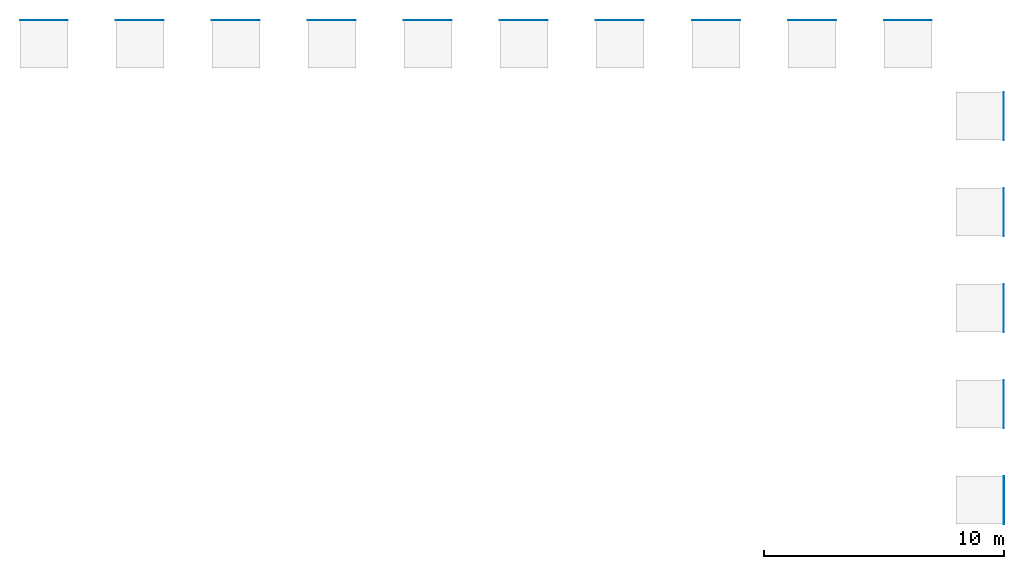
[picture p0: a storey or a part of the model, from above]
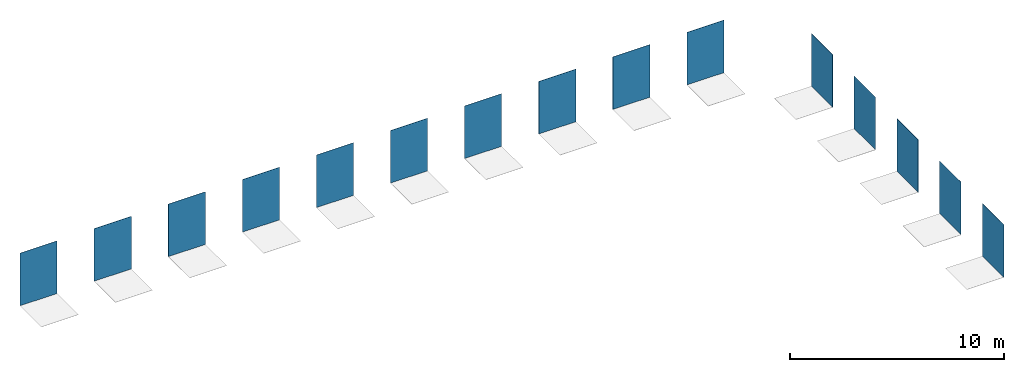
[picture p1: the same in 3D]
Properties of the parts of a building model (IFC2X3), part 2 of 2

# IfcWallStandardCase: Basic Wall:PGR_Porcelanosa_CeramicTiles_Ascot_Arce-193x1200mm-100161043, Basic Wall:PGR_Porcelanosa_CeramicTiles_Ascot_Arce-193x1200mm-100161043:215110
Type - NBS_Data - HasSurfaceRoughness: no; AbrasionResistance: 4: Light-External Access; BreakingStrength: Average Value: 3310 N (Min. 1300 N); ChemicalResistance: Class 'A' for swimming pools and cleaning products (resists attack); minimum Class 'B' for acids and bases; Collection: PAR-KER; CreationDate: 2018/07; Dcof: >0.42; FlexuralStrength: >40 N/mm²; FrostResistance: Conforms to ISO 10545-9; Group: BIa; MoistureExpansion: <0.1 mm/m; RampTest: R-10; RecycledContent: >6.5%; Series: Ascot; SlipResistanceValuePendulumTestValue: CL1; StainResistance: Class 5: Easy cleaning with water; SurfaceQuality: Without surface defects; ThermalShockResistance: Conforms to ISO 10545–12; UpecC: n/a; UpecE: n/a; UpecP: n/a; UpecU: n/a; WaterAbsorption: E<=0.5%
COBie - AssetIdentifier: n/a; BarCode: n/a; InstallationDate: 1900-12-31T23:59:59; TagNumber: n/a; WarrantyStartDate: 1900-12-31T23:59:59

# IfcWallStandardCase: Basic Wall:PGR_Porcelanosa_CeramicTiles_Ascot_Arce-294x1200mm-100161044, Basic Wall:PGR_Porcelanosa_CeramicTiles_Ascot_Arce-294x1200mm-100161044:215111
In: Level 1
Type - PredefinedType: STANDARD; Material: PGR_Porcelanosa_CeramicTiles_Ascot_Arce-294x1200mm-100161044 11 mm
Type - NBS_General - Author: Porcelanosa Group; BIMObjectName: PGR_Porcelanosa_CeramicTiles_Ascot_Arce-294x1200mm-100161044; ManufacturerURL: www.porcelanosa.com; NBSDescription: Ceramic Tiles; NBSReference: 45-80-95/310; ProductInformation: http://calidad.info-grupo.com:8081/GeneraFicha3/PDF?articulo=100161044&lang=EN&un=0; Revision: n/a; Uniclass2015Code: Pr_35_93_96_19; Uniclass2015Title: Ceramic Tiles; Uniclass2015Version: Products v1.5; Version: 1
Type - COBie - AccessibilityPerformance: See ProductInformation (Technical PDF); AssetType: Fixed; Category: Walls; CodePerformance: ISO-13006:2012; UNE-EN 14411:2012; Color: Marron; Constituents: Clays, feldespat and glaze; Description: Rectified Porcelain tiles, ASCOT series from PORCELANOSA, MARRON color and MATTE finish, 29.4x120 cm (11.5 mm thickness), group BIa, according to UNE-EN 14411, water absortion capacity E<=0.5%, flexural strength >40 N/mm², breaking strength with an average value of 3310 N (Min. 1300 N) and slip resistance R-10; DurationUnit: year; ExpectedLife: 50; Features: See ProductInformation (Technical PDF); Grade: First quality; Manufacturer: bim.gp@porcelanosagrupo.com; ModelNumber: 100161044; ModelReference: Ascot Arce 29.4x120 cm; Name: CeramicTiles_Ascot_Arce-294x1200mm-100161044; NominalHeight: 11.5 mm; NominalLength: 1200 mm; NominalWidth: 294 mm; ReplacementCost: n/a; Shape: Rectangular; Size: 294x1200x11.5 mm; Sustainability Performance: See ProductInformation (Technical PDF); WarrantyDescription: Manufacturer warranty, applicable worldwide, with the pertinent national legislation prevailing in all cases and covering at least a 3-year period; all products must have been manufactured and fitted in accordance with the Fabricator's Manual, and have been used and cared for in accordance with the Guide to Use, Cleaning and Care available on the web page www.porcelanosa.com; WarrantyDurationLabor: n/a; WarrantyDurationParts: 3; WarrantyDurationUnit: year; WarrantyGuarantorLabor: n/a; WarrantyGuarantorParts: bim.gp@porcelanosagrupo.com
Type - Pset_CoveringCommon - IsExternal: yes; Reference: n/a; AcousticRating: n/a; Finish: Tone Variations, Matte, Rectified, Wood; FireRating: A1; FlammabilityRating: Class 0; FragilityRating: n/a; Material: Ceramic; SurfaceSpreadOfFlame: Class 0; ThermalTransmittance: 200 kg/K/s3; TotalThickness: 11.5 mm
Type - IFC - IfcExportType: FLOORING; IfcExportAS: IfcCovering
Type - NBS_Data - HasSurfaceRoughness: no; AbrasionResistance: 4: Light-External Access; BreakingStrength: Average Value: 3310 N (Min. 1300 N); ChemicalResistance: Class 'A' for swimming pools and cleaning products (resists attack); minimum Class 'B' for acids and bases; Collection: PAR-KER; CreationDate: 2018/07; Dcof: >0.42; FlexuralStrength: >40 N/mm²; FrostResistance: Conforms to ISO 10545-9; Group: BIa; MoistureExpansion: <0.1 mm/m; RampTest: R-10; RecycledContent: >6.5%; Series: Ascot; SlipResistanceValuePendulumTestValue: CL1; StainResistance: Class 5: Easy cleaning with water; SurfaceQuality: Without surface defects; ThermalShockResistance: Conforms to ISO 10545–12; UpecC: 2; UpecE: 3; UpecP: 3; UpecU: 3; WaterAbsorption: E<=0.5%
COBie - AssetIdentifier: n/a; BarCode: n/a; InstallationDate: 1900-12-31T23:59:59; TagNumber: n/a; WarrantyStartDate: 1900-12-31T23:59:59

# IfcWallStandardCase: Basic Wall:PGR_Porcelanosa_CeramicTiles_Ascot_Arce_Ant.-193x1200mm-100161045, Basic Wall:PGR_Porcelanosa_CeramicTiles_Ascot_Arce_Ant.-193x1200mm-100161045:215112
In: Level 1
Type - PredefinedType: STANDARD; Material: PGR_Porcelanosa_CeramicTiles_Ascot_Arce_Ant.-193x1200mm-100161045 11 mm
Type - NBS_General - Author: Porcelanosa Group; BIMObjectName: PGR_Porcelanosa_CeramicTiles_Ascot_Arce_Ant.-193x1200mm-100161045; ManufacturerURL: www.porcelanosa.com; NBSDescription: Ceramic Tiles; NBSReference: 45-80-95/310; ProductInformation: http://calidad.info-grupo.com:8081/GeneraFicha3/PDF?articulo=100161045&lang=EN&un=0; Revision: n/a; Uniclass2015Code: Pr_35_93_96_19; Uniclass2015Title: Ceramic Tiles; Uniclass2015Version: Products v1.5; Version: 1
Type - COBie - AccessibilityPerformance: See ProductInformation (Technical PDF); AssetType: Fixed; Category: Pr_35_93_96_19:Ceramic Tiles; CodePerformance: ISO-13006:2012; UNE-EN 14411:2012; Color: Marron; Constituents: Clays, feldespat and glaze; Description: Rectified Porcelain tiles, ASCOT series from PORCELANOSA, MARRON color and MATTE finish, 19.3x120 cm (11.5 mm thickness), group BIa, according to UNE-EN 14411, water absortion capacity E<=0.5%, flexural strength >40 N/mm², breaking strength with an average value of 3310 N (Min. 1300 N) and slip resistance R-12; DurationUnit: year; ExpectedLife: 50; Features: See ProductInformation (Technical PDF); Grade: First quality; Manufacturer: bim.gp@porcelanosagrupo.com; ModelNumber: 100161045; ModelReference: Ascot Arce Ant. 19.3x120 cm; Name: CeramicTiles_Ascot_Arce_Ant.-193x1200mm-100161045; NominalHeight: 11.5 mm; NominalLength: 1200 mm; NominalWidth: 193 mm; ReplacementCost: n/a; Shape: Rectangular; Size: 193x1200x11.5 mm; Sustainability Performance: See ProductInformation (Technical PDF); WarrantyDescription: Manufacturer warranty, applicable worldwide, with the pertinent national legislation prevailing in all cases and covering at least a 3-year period; all products must have been manufactured and fitted in accordance with the Fabricator's Manual, and have been used and cared for in accordance with the Guide to Use, Cleaning and Care available on the web page www.porcelanosa.com; WarrantyDurationLabor: n/a; WarrantyDurationParts: 3; WarrantyDurationUnit: year; WarrantyGuarantorLabor: n/a; WarrantyGuarantorParts: bim.gp@porcelanosagrupo.com
Type - Pset_CoveringCommon - IsExternal: yes; Reference: n/a; AcousticRating: n/a; Finish: Tone Variations, Matte, Non-Slip, Rectified, Wood; FireRating: A1; FlammabilityRating: Class 0; FragilityRating: n/a; Material: Ceramic; SurfaceSpreadOfFlame: Class 0; ThermalTransmittance: 200 kg/K/s3; TotalThickness: 11.5 mm
Type - IFC - IfcExportType: FLOORING; IfcExportAS: IfcCovering
Type - NBS_Data - HasSurfaceRoughness: no; AbrasionResistance: 4: Light-External Access; BreakingStrength: Average Value: 3310 N (Min. 1300 N); ChemicalResistance: Class 'A' for swimming pools and cleaning products (resists attack); minimum Class 'B' for acids and bases; Collection: PAR-KER; CreationDate: 2018/07; Dcof: >0.42; FlexuralStrength: >40 N/mm²; FrostResistance: Conforms to ISO 10545-9; Group: BIa; MoistureExpansion: <0.1 mm/m; RampTest: R-12; RecycledContent: >6.5%; Series: Ascot; SlipResistanceValuePendulumTestValue: CL3; StainResistance: Class 5: Easy cleaning with water; SurfaceQuality: Without surface defects; ThermalShockResistance: Conforms to ISO 10545–12; UpecC: n/a; UpecE: n/a; UpecP: n/a; UpecU: n/a; WaterAbsorption: E<=0.5%
COBie - AssetIdentifier: n/a; BarCode: n/a; InstallationDate: 1900-12-31T23:59:59; TagNumber: n/a; WarrantyStartDate: 1900-12-31T23:59:59

# IfcWallStandardCase: Basic Wall:PGR_Porcelanosa_CeramicTiles_Ascot_Grey-193x1200mm-100161025, Basic Wall:PGR_Porcelanosa_CeramicTiles_Ascot_Grey-193x1200mm-100161025:212342
In: Level 1
Type - PredefinedType: STANDARD; Material: PGR_Porcelanosa_CeramicTiles_Ascot_Grey-193x1200mm-100161025 12 mm
Type - NBS_General - Author: Porcelanosa Group; BIMObjectName: PGR_Porcelanosa_CeramicTiles_Ascot_Grey-193x1200mm-100161025; ManufacturerURL: www.porcelanosa.com; NBSDescription: Ceramic Tiles; NBSReference: 45-80-95/310; ProductInformation: http://calidad.info-grupo.com:8081/GeneraFicha3/PDF?articulo=100161025&lang=EN&un=0; Revision: n/a; Uniclass2015Code: Pr_35_93_96_19; Uniclass2015Title: Ceramic Tiles; Uniclass2015Version: Products v1.5; Version: 1
Type - COBie - AccessibilityPerformance: See ProductInformation (Technical PDF); AssetType: Fixed; Category: Walls; CodePerformance: ISO-13006:2012; UNE-EN 14411:2012; Color: Gris; Constituents: Clays, feldespat and glaze; Description: Rectified Porcelain tiles, ASCOT series from PORCELANOSA, GRIS color and MATTE finish, 19.3x120 cm (11.5 mm thickness), group BIa, according to UNE-EN 14411, water absortion capacity E<=0.5%, flexural strength >40 N/mm², breaking strength with an average value of 3310 N (Min. 1300 N) and slip resistance R-10; DurationUnit: year; ExpectedLife: 50; Features: See ProductInformation (Technical PDF); Grade: First quality; Manufacturer: bim.gp@porcelanosagrupo.com; ModelNumber: 100161025; ModelReference: Ascot Grey 19.3x120 cm; Name: CeramicTiles_Ascot_Grey-193x1200mm-100161025; NominalHeight: 11.5 mm; NominalLength: 1200 mm; NominalWidth: 193 mm; ReplacementCost: n/a; Shape: Rectangular; Size: 193x1200x11.5 mm; Sustainability Performance: See ProductInformation (Technical PDF); WarrantyDescription: Manufacturer warranty, applicable worldwide, with the pertinent national legislation prevailing in all cases and covering at least a 3-year period; all products must have been manufactured and fitted in accordance with the Fabricator's Manual, and have been used and cared for in accordance with the Guide to Use, Cleaning and Care available on the web page www.porcelanosa.com; WarrantyDurationLabor: n/a; WarrantyDurationParts: 3; WarrantyDurationUnit: year; WarrantyGuarantorLabor: n/a; WarrantyGuarantorParts: bim.gp@porcelanosagrupo.com
Type - Pset_CoveringCommon - IsExternal: yes; Reference: n/a; AcousticRating: n/a; Finish: Tone Variations, Matte, Rectified, Wood; FireRating: A1; FlammabilityRating: Class 0; FragilityRating: n/a; Material: Ceramic; SurfaceSpreadOfFlame: Class 0; ThermalTransmittance: 200 kg/K/s3; TotalThickness: 11.5 mm
Type - IFC - IfcExportType: FLOORING; IfcExportAS: IfcCovering
Type - NBS_Data - HasSurfaceRoughness: no; AbrasionResistance: 4: Light-External Access; BreakingStrength: Average Value: 3310 N (Min. 1300 N); ChemicalResistance: Class 'A' for swimming pools and cleaning products (resists attack); minimum Class 'B' for acids and bases; Collection: PAR-KER; CreationDate: 2018/07; Dcof: >0.42; FlexuralStrength: >40 N/mm²; FrostResistance: Conforms to ISO 10545-9; Group: BIa; MoistureExpansion: <0.1 mm/m; RampTest: R-10; RecycledContent: >6.5%; Series: Ascot; SlipResistanceValuePendulumTestValue: CL1; StainResistance: Class 5: Easy cleaning with water; SurfaceQuality: Without surface defects; ThermalShockResistance: Conforms to ISO 10545–12; UpecC: n/a; UpecE: n/a; UpecP: n/a; UpecU: n/a; WaterAbsorption: E<=0.5%
COBie - AssetIdentifier: n/a; BarCode: n/a; InstallationDate: 1900-12-31T23:59:59; TagNumber: n/a; WarrantyStartDate: 1900-12-31T23:59:59

# IfcWallStandardCase: Basic Wall:PGR_Porcelanosa_CeramicTiles_Ascot_Grey-294x1200mm-100161120, Basic Wall:PGR_Porcelanosa_CeramicTiles_Ascot_Grey-294x1200mm-100161120:212256
In: Level 1
Type - PredefinedType: STANDARD; Material: PGR_Porcelanosa_CeramicTiles_Ascot_Grey-294x1200mm-100161120 12 mm
Type - NBS_General - Author: Porcelanosa Group; BIMObjectName: PGR_Porcelanosa_CeramicTiles_Ascot_Grey-294x1200mm-100161120; ManufacturerURL: www.porcelanosa.com; NBSDescription: Ceramic Tiles; NBSReference: 45-80-95/310; ProductInformation: http://calidad.info-grupo.com:8081/GeneraFicha3/PDF?articulo=100161120&lang=EN&un=0; Revision: n/a; Uniclass2015Code: Pr_35_93_96_19; Uniclass2015Title: Ceramic Tiles; Uniclass2015Version: Products v1.5; Version: 1
Type - COBie - AccessibilityPerformance: See ProductInformation (Technical PDF); AssetType: Fixed; Category: Pr_35_93_96_19:Ceramic Tiles; CodePerformance: ISO-13006:2012; UNE-EN 14411:2012; Color: Gris; Constituents: Clays, feldespat and glaze; Description: Rectified Porcelain tiles, ASCOT series from PORCELANOSA, GRIS color and MATTE finish, 29.4x120 cm (11.5 mm thickness), group BIa, according to UNE-EN 14411, water absortion capacity E<=0.5%, flexural strength >40 N/mm², breaking strength with an average value of 3310 N (Min. 1300 N) and slip resistance R-10; DurationUnit: year; ExpectedLife: 50; Features: See ProductInformation (Technical PDF); Grade: First quality; Manufacturer: bim.gp@porcelanosagrupo.com; ModelNumber: 100161120; ModelReference: Ascot Grey 29.4x120 cm; Name: CeramicTiles_Ascot_Grey-294x1200mm-100161120; NominalHeight: 11.5 mm; NominalLength: 1200 mm; NominalWidth: 294 mm; ReplacementCost: n/a; Shape: Rectangular; Size: 294x1200x11.5 mm; Sustainability Performance: See ProductInformation (Technical PDF); WarrantyDescription: Manufacturer warranty, applicable worldwide, with the pertinent national legislation prevailing in all cases and covering at least a 3-year period; all products must have been manufactured and fitted in accordance with the Fabricator's Manual, and have been used and cared for in accordance with the Guide to Use, Cleaning and Care available on the web page www.porcelanosa.com; WarrantyDurationLabor: n/a; WarrantyDurationParts: 3; WarrantyDurationUnit: year; WarrantyGuarantorLabor: n/a; WarrantyGuarantorParts: bim.gp@porcelanosagrupo.com
Type - Pset_CoveringCommon - IsExternal: yes; Reference: n/a; AcousticRating: n/a; Finish: Tone Variations, Matte, Rectified, Wood; FireRating: A1; FlammabilityRating: Class 0; FragilityRating: n/a; Material: Ceramic; SurfaceSpreadOfFlame: Class 0; ThermalTransmittance: 200 kg/K/s3; TotalThickness: 11.5 mm
Type - IFC - IfcExportType: FLOORING; IfcExportAS: IfcCovering
Type - NBS_Data - HasSurfaceRoughness: no; AbrasionResistance: 4: Light-External Access; BreakingStrength: Average Value: 3310 N (Min. 1300 N); ChemicalResistance: Class 'A' for swimming pools and cleaning products (resists attack); minimum Class 'B' for acids and bases; Collection: PAR-KER; CreationDate: 2018/07; Dcof: >0.42; FlexuralStrength: >40 N/mm²; FrostResistance: Conforms to ISO 10545-9; Group: BIa; MoistureExpansion: <0.1 mm/m; RampTest: R-10; RecycledContent: >6.5%; Series: Ascot; SlipResistanceValuePendulumTestValue: CL1; StainResistance: Class 5: Easy cleaning with water; SurfaceQuality: Without surface defects; ThermalShockResistance: Conforms to ISO 10545–12; UpecC: 2; UpecE: 3; UpecP: 3; UpecU: 2S; WaterAbsorption: E<=0.5%
COBie - AssetIdentifier: n/a; BarCode: n/a; InstallationDate: 1900-12-31T23:59:59; TagNumber: n/a; WarrantyStartDate: 1900-12-31T23:59:59

# IfcWallStandardCase: Basic Wall:PGR_Porcelanosa_CeramicTiles_Ascot_Grey_Ant.-193x1200mm-100161026, Basic Wall:PGR_Porcelanosa_CeramicTiles_Ascot_Grey_Ant.-193x1200mm-100161026:213212
In: Level 1
Type - PredefinedType: STANDARD; Material: PGR_Porcelanosa_CeramicTiles_Ascot_Grey_Ant.-193x1200mm-100161026 12 mm
Type - NBS_General - Author: Porcelanosa Group; BIMObjectName: PGR_Porcelanosa_CeramicTiles_Ascot_Grey_Ant.-193x1200mm-100161026; ManufacturerURL: www.porcelanosa.com; NBSDescription: Ceramic Tiles; NBSReference: 45-80-95/310; ProductInformation: http://calidad.info-grupo.com:8081/GeneraFicha3/PDF?articulo=100161026&lang=EN&un=0; Revision: n/a; Uniclass2015Code: Pr_35_93_96_19; Uniclass2015Title: Ceramic Tiles; Uniclass2015Version: Products v1.5; Version: 1
Type - COBie - AccessibilityPerformance: See ProductInformation (Technical PDF); AssetType: Fixed; Category: Walls; CodePerformance: ISO-13006:2012; UNE-EN 14411:2012; Color: Gris; Constituents: Clays, feldespat and glaze; Description: Rectified Porcelain tiles, ASCOT series from PORCELANOSA, GRIS color and MATTE finish, 19.3x120 cm (11.5 mm thickness), group BIa, according to UNE-EN 14411, water absortion capacity E<=0.5%, flexural strength >40 N/mm², breaking strength with an average value of 3310 N (Min. 1300 N) and slip resistance R-12; DurationUnit: year; ExpectedLife: 50; Features: See ProductInformation (Technical PDF); Grade: First quality; Manufacturer: bim.gp@porcelanosagrupo.com; ModelNumber: 100161026; ModelReference: Ascot Grey Ant. 19.3x120 cm; Name: CeramicTiles_Ascot_Grey_Ant.-193x1200mm-100161026; NominalHeight: 11.5 mm; NominalLength: 1200 mm; NominalWidth: 193 mm; ReplacementCost: n/a; Shape: Rectangular; Size: 193x1200x11.5 mm; Sustainability Performance: See ProductInformation (Technical PDF); WarrantyDescription: Manufacturer warranty, applicable worldwide, with the pertinent national legislation prevailing in all cases and covering at least a 3-year period; all products must have been manufactured and fitted in accordance with the Fabricator's Manual, and have been used and cared for in accordance with the Guide to Use, Cleaning and Care available on the web page www.porcelanosa.com; WarrantyDurationLabor: n/a; WarrantyDurationParts: 3; WarrantyDurationUnit: year; WarrantyGuarantorLabor: n/a; WarrantyGuarantorParts: bim.gp@porcelanosagrupo.com
Type - Pset_CoveringCommon - IsExternal: yes; Reference: n/a; AcousticRating: n/a; Finish: Tone Variations, Matte, Non-Slip, Rectified, Wood; FireRating: A1; FlammabilityRating: Class 0; FragilityRating: n/a; Material: Ceramic; SurfaceSpreadOfFlame: Class 0; ThermalTransmittance: 200 kg/K/s3; TotalThickness: 11.5 mm
Type - IFC - IfcExportType: FLOORING; IfcExportAS: IfcCovering
Type - NBS_Data - HasSurfaceRoughness: no; AbrasionResistance: 4: Light-External Access; BreakingStrength: Average Value: 3310 N (Min. 1300 N); ChemicalResistance: Class 'A' for swimming pools and cleaning products (resists attack); minimum Class 'B' for acids and bases; Collection: PAR-KER; CreationDate: 2018/07; Dcof: >0.42; FlexuralStrength: >40 N/mm²; FrostResistance: Conforms to ISO 10545-9; Group: BIa; MoistureExpansion: <0.1 mm/m; RampTest: R-12; RecycledContent: >6.5%; Series: Ascot; SlipResistanceValuePendulumTestValue: CL3; StainResistance: Class 5: Easy cleaning with water; SurfaceQuality: Without surface defects; ThermalShockResistance: Conforms to ISO 10545–12; UpecC: n/a; UpecE: n/a; UpecP: n/a; UpecU: n/a; WaterAbsorption: E<=0.5%
COBie - AssetIdentifier: n/a; BarCode: n/a; InstallationDate: 1900-12-31T23:59:59; TagNumber: n/a; WarrantyStartDate: 1900-12-31T23:59:59

# IfcWallStandardCase: Basic Wall:PGR_Porcelanosa_CeramicTiles_Ascot_Olivo-193x1200mm-100161027, Basic Wall:PGR_Porcelanosa_CeramicTiles_Ascot_Olivo-193x1200mm-100161027:209160
In: Level 1
Type - PredefinedType: STANDARD; Material: PGR_Porcelanosa_CeramicTiles_Ascot_Olivo-193x1200mm-100161027 12 mm
Type - NBS_General - Author: Porcelanosa Group; BIMObjectName: PGR_Porcelanosa_CeramicTiles_Ascot_Olivo-193x1200mm-100161027; ManufacturerURL: www.porcelanosa.com; NBSDescription: Ceramic Tiles; NBSReference: 45-80-95/310; ProductInformation: http://calidad.info-grupo.com:8081/GeneraFicha3/PDF?articulo=100161027&lang=EN&un=0; Revision: n/a; Uniclass2015Code: Pr_35_93_96_19; Uniclass2015Title: Ceramic Tiles; Uniclass2015Version: Products v1.5; Version: 1
Type - COBie - AccessibilityPerformance: See ProductInformation (Technical PDF); AssetType: Fixed; Category: Walls; CodePerformance: ISO-13006:2012; UNE-EN 14411:2012; Color: Gris; Constituents: Clays, feldespat and glaze; Description: Rectified Porcelain tiles, ASCOT series from PORCELANOSA, GRIS color and MATTE finish, 19.3x120 cm (11.5 mm thickness), group BIa, according to UNE-EN 14411, water absortion capacity E<=0.5%, flexural strength >40 N/mm², breaking strength with an average value of 3310 N (Min. 1300 N) and slip resistance R-10; DurationUnit: year; ExpectedLife: 50; Features: See ProductInformation (Technical PDF); Grade: First quality; Manufacturer: bim.gp@porcelanosagrupo.com; ModelNumber: 100161027; ModelReference: Ascot Olivo 19.3x120 cm; Name: CeramicTiles_Ascot_Olivo-193x1200mm-100161027; NominalHeight: 11.5 mm; NominalLength: 1200 mm; NominalWidth: 193 mm; ReplacementCost: n/a; Shape: Rectangular; Size: 193x1200x11.5 mm; Sustainability Performance: See ProductInformation (Technical PDF); WarrantyDescription: Manufacturer warranty, applicable worldwide, with the pertinent national legislation prevailing in all cases and covering at least a 3-year period; all products must have been manufactured and fitted in accordance with the Fabricator's Manual, and have been used and cared for in accordance with the Guide to Use, Cleaning and Care available on the web page www.porcelanosa.com; WarrantyDurationLabor: n/a; WarrantyDurationParts: 3; WarrantyDurationUnit: year; WarrantyGuarantorLabor: n/a; WarrantyGuarantorParts: bim.gp@porcelanosagrupo.com
Type - Pset_CoveringCommon - IsExternal: yes; Reference: n/a; AcousticRating: n/a; Finish: Tone Variations, Matte, Rectified, Wood; FireRating: A1; FlammabilityRating: Class 0; FragilityRating: n/a; Material: Ceramic; SurfaceSpreadOfFlame: Class 0; ThermalTransmittance: 200 kg/K/s3; TotalThickness: 11.5 mm
Type - IFC - IfcExportType: FLOORING; IfcExportAS: IfcCovering
Type - NBS_Data - HasSurfaceRoughness: no; AbrasionResistance: 4: Light-External Access; BreakingStrength: Average Value: 3310 N (Min. 1300 N); ChemicalResistance: Class 'A' for swimming pools and cleaning products (resists attack); minimum Class 'B' for acids and bases; Collection: PAR-KER; CreationDate: 2018/07; Dcof: >0.42; FlexuralStrength: >40 N/mm²; FrostResistance: Conforms to ISO 10545-9; Group: BIa; MoistureExpansion: <0.1 mm/m; RampTest: R-10; RecycledContent: >6.5%; Series: Ascot; SlipResistanceValuePendulumTestValue: CL1; StainResistance: Class 5: Easy cleaning with water; SurfaceQuality: Without surface defects; ThermalShockResistance: Conforms to ISO 10545–12; UpecC: n/a; UpecE: n/a; UpecP: n/a; UpecU: n/a; WaterAbsorption: E<=0.5%
COBie - AssetIdentifier: n/a; BarCode: n/a; InstallationDate: 1900-12-31T23:59:59; TagNumber: n/a; WarrantyStartDate: 1900-12-31T23:59:59

# IfcWallStandardCase: Basic Wall:PGR_Porcelanosa_CeramicTiles_Ascot_Olivo-294x1200mm-100161121, Basic Wall:PGR_Porcelanosa_CeramicTiles_Ascot_Olivo-294x1200mm-100161121:209127
In: Level 1
Type - PredefinedType: STANDARD; Material: PGR_Porcelanosa_CeramicTiles_Ascot_Olivo-294x1200mm-100161121 12 mm
Type - NBS_General - Author: Porcelanosa Group; BIMObjectName: PGR_Porcelanosa_CeramicTiles_Ascot_Olivo-294x1200mm-100161121; ManufacturerURL: www.porcelanosa.com; NBSDescription: Ceramic Tiles; NBSReference: 45-80-95/310; ProductInformation: http://calidad.info-grupo.com:8081/GeneraFicha3/PDF?articulo=100161121&lang=EN&un=0; Revision: n/a; Uniclass2015Code: Pr_35_93_96_19; Uniclass2015Title: Ceramic Tiles; Uniclass2015Version: Products v1.5; Version: 1
Type - COBie - AccessibilityPerformance: See ProductInformation (Technical PDF); AssetType: Fixed; Category: Walls; CodePerformance: ISO-13006:2012; UNE-EN 14411:2012; Color: Marron; Constituents: Clays, feldespat and glaze; Description: Rectified Porcelain tiles, ASCOT series from PORCELANOSA, MARRON color and MATTE finish, 29.4x120 cm (11.5 mm thickness), group BIa, according to UNE-EN 14411, water absortion capacity E<=0.5%, flexural strength >40 N/mm², breaking strength with an average value of 3310 N (Min. 1300 N) and slip resistance R-10; DurationUnit: year; ExpectedLife: 50; Features: See ProductInformation (Technical PDF); Grade: First quality; Manufacturer: bim.gp@porcelanosagrupo.com; ModelNumber: 100161121; ModelReference: Ascot Olivo 29.4x120 cm; Name: CeramicTiles_Ascot_Olivo-294x1200mm-100161121; NominalHeight: 11.5 mm; NominalLength: 1200 mm; NominalWidth: 294 mm; ReplacementCost: n/a; Shape: Rectangular; Size: 294x1200x11.5 mm; Sustainability Performance: See ProductInformation (Technical PDF); WarrantyDescription: Manufacturer warranty, applicable worldwide, with the pertinent national legislation prevailing in all cases and covering at least a 3-year period; all products must have been manufactured and fitted in accordance with the Fabricator's Manual, and have been used and cared for in accordance with the Guide to Use, Cleaning and Care available on the web page www.porcelanosa.com; WarrantyDurationLabor: n/a; WarrantyDurationParts: 3; WarrantyDurationUnit: year; WarrantyGuarantorLabor: n/a; WarrantyGuarantorParts: bim.gp@porcelanosagrupo.com
Type - Pset_CoveringCommon - IsExternal: yes; Reference: n/a; AcousticRating: n/a; Finish: Tone Variations, Matte, Rectified, Wood; FireRating: A1; FlammabilityRating: Class 0; FragilityRating: n/a; Material: Ceramic; SurfaceSpreadOfFlame: Class 0; ThermalTransmittance: 200 kg/K/s3; TotalThickness: 11.5 mm
Type - IFC - IfcExportType: FLOORING; IfcExportAS: IfcCovering
Type - NBS_Data - HasSurfaceRoughness: no; AbrasionResistance: 4: Light-External Access; BreakingStrength: Average Value: 3310 N (Min. 1300 N); ChemicalResistance: Class 'A' for swimming pools and cleaning products (resists attack); minimum Class 'B' for acids and bases; Collection: PAR-KER; CreationDate: 2018/07; Dcof: >0.42; FlexuralStrength: >40 N/mm²; FrostResistance: Conforms to ISO 10545-9; Group: BIa; MoistureExpansion: <0.1 mm/m; RampTest: R-10; RecycledContent: >6.5%; Series: Ascot; SlipResistanceValuePendulumTestValue: CL1; StainResistance: Class 5: Easy cleaning with water; SurfaceQuality: Without surface defects; ThermalShockResistance: Conforms to ISO 10545–12; UpecC: 2; UpecE: 3; UpecP: 3; UpecU: 2S; WaterAbsorption: E<=0.5%
COBie - AssetIdentifier: n/a; BarCode: n/a; InstallationDate: 1900-12-31T23:59:59; TagNumber: n/a; WarrantyStartDate: 1900-12-31T23:59:59

# IfcWallStandardCase: Basic Wall:PGR_Porcelanosa_CeramicTiles_Ascot_Olivo_Ant.-193x1200mm-100161028, Basic Wall:PGR_Porcelanosa_CeramicTiles_Ascot_Olivo_Ant.-193x1200mm-100161028:213224
In: Level 1
Type - PredefinedType: STANDARD; Material: PGR_Porcelanosa_CeramicTiles_Ascot_Olivo_Ant.-193x1200mm-100161028 12 mm
Type - NBS_General - Author: Porcelanosa Group; BIMObjectName: PGR_Porcelanosa_CeramicTiles_Ascot_Olivo_Ant.-193x1200mm-100161028; ManufacturerURL: www.porcelanosa.com; NBSDescription: Ceramic Tiles; NBSReference: 45-80-95/310; ProductInformation: http://calidad.info-grupo.com:8081/GeneraFicha3/PDF?articulo=100161028&lang=EN&un=0; Revision: n/a; Uniclass2015Code: Pr_35_93_96_19; Uniclass2015Title: Ceramic Tiles; Uniclass2015Version: Products v1.5; Version: 1
Type - COBie - AccessibilityPerformance: See ProductInformation (Technical PDF); AssetType: Fixed; Category: Walls; CodePerformance: ISO-13006:2012; UNE-EN 14411:2012; Color: Gris; Constituents: Clays, feldespat and glaze; Description: Rectified Porcelain tiles, ASCOT series from PORCELANOSA, GRIS color and MATTE finish, 19.3x120 cm (11.5 mm thickness), group BIa, according to UNE-EN 14411, water absortion capacity E<=0.5%, flexural strength >40 N/mm², breaking strength with an average value of 3310 N (Min. 1300 N) and slip resistance R-12; DurationUnit: year; ExpectedLife: 50; Features: See ProductInformation (Technical PDF); Grade: First quality; Manufacturer: bim.gp@porcelanosagrupo.com; ModelNumber: 100161028; ModelReference: Ascot Olivo Ant. 19.3x120 cm; Name: CeramicTiles_Ascot_Olivo_Ant.-193x1200mm-100161028; NominalHeight: 11.5 mm; NominalLength: 1200 mm; NominalWidth: 193 mm; ReplacementCost: n/a; Shape: Rectangular; Size: 193x1200x11.5 mm; Sustainability Performance: See ProductInformation (Technical PDF); WarrantyDescription: Manufacturer warranty, applicable worldwide, with the pertinent national legislation prevailing in all cases and covering at least a 3-year period; all products must have been manufactured and fitted in accordance with the Fabricator's Manual, and have been used and cared for in accordance with the Guide to Use, Cleaning and Care available on the web page www.porcelanosa.com; WarrantyDurationLabor: n/a; WarrantyDurationParts: 3; WarrantyDurationUnit: year; WarrantyGuarantorLabor: n/a; WarrantyGuarantorParts: bim.gp@porcelanosagrupo.com
Type - Pset_CoveringCommon - IsExternal: yes; Reference: n/a; AcousticRating: n/a; Finish: Tone Variations, Matte, Non-Slip, Rectified, Wood; FireRating: A1; FlammabilityRating: Class 0; FragilityRating: n/a; Material: Ceramic; SurfaceSpreadOfFlame: Class 0; ThermalTransmittance: 200 kg/K/s3; TotalThickness: 11.5 mm
Type - IFC - IfcExportType: FLOORING; IfcExportAS: IfcCovering
Type - NBS_Data - HasSurfaceRoughness: no; AbrasionResistance: 4: Light-External Access; BreakingStrength: Average Value: 3310 N (Min. 1300 N); ChemicalResistance: Class 'A' for swimming pools and cleaning products (resists attack); minimum Class 'B' for acids and bases; Collection: PAR-KER; CreationDate: 2018/07; Dcof: >0.42; FlexuralStrength: >40 N/mm²; FrostResistance: Conforms to ISO 10545-9; Group: BIa; MoistureExpansion: <0.1 mm/m; RampTest: R-12; RecycledContent: >6.5%; Series: Ascot; SlipResistanceValuePendulumTestValue: CL3; StainResistance: Class 5: Easy cleaning with water; SurfaceQuality: Without surface defects; ThermalShockResistance: Conforms to ISO 10545–12; UpecC: n/a; UpecE: n/a; UpecP: n/a; UpecU: n/a; WaterAbsorption: E<=0.5%
COBie - AssetIdentifier: n/a; BarCode: n/a; InstallationDate: 1900-12-31T23:59:59; TagNumber: n/a; WarrantyStartDate: 1900-12-31T23:59:59

# IfcWallStandardCase: Basic Wall:PGR_Porcelanosa_CeramicTiles_Ascot_Roble-193x1200mm-100161029, Basic Wall:PGR_Porcelanosa_CeramicTiles_Ascot_Roble-193x1200mm-100161029:215113
In: Level 1
Type - PredefinedType: STANDARD; Material: PGR_Porcelanosa_CeramicTiles_Ascot_Roble-193x1200mm-100161029 11 mm
Type - NBS_General - Author: Porcelanosa Group; BIMObjectName: PGR_Porcelanosa_CeramicTiles_Ascot_Roble-193x1200mm-100161029; ManufacturerURL: www.porcelanosa.com; NBSDescription: Ceramic Tiles; NBSReference: 45-80-95/310; ProductInformation: http://calidad.info-grupo.com:8081/GeneraFicha3/PDF?articulo=100161029&lang=EN&un=0; Revision: n/a; Uniclass2015Code: Pr_35_93_96_19; Uniclass2015Title: Ceramic Tiles; Uniclass2015Version: Products v1.5; Version: 1
Type - COBie - AccessibilityPerformance: See ProductInformation (Technical PDF); AssetType: Fixed; Category: Pr_35_93_96_19:Ceramic Tiles; CodePerformance: ISO-13006:2012; UNE-EN 14411:2012; Color: Marron; Constituents: Clays, feldespat and glaze; Description: Rectified Porcelain tiles, ASCOT series from PORCELANOSA, MARRON color and MATTE finish, 19.3x120 cm (11.5 mm thickness), group BIa, according to UNE-EN 14411, water absortion capacity E<=0.5%, flexural strength >40 N/mm², breaking strength with an average value of 3310 N (Min. 1300 N) and slip resistance R-10; DurationUnit: year; ExpectedLife: 50; Features: See ProductInformation (Technical PDF); Grade: First quality; Manufacturer: bim.gp@porcelanosagrupo.com; ModelNumber: 100161029; ModelReference: Ascot Roble 19.3x120 cm; Name: CeramicTiles_Ascot_Roble-193x1200mm-100161029; NominalHeight: 11.5 mm; NominalLength: 1200 mm; NominalWidth: 193 mm; ReplacementCost: n/a; Shape: Rectangular; Size: 193x1200x11.5 mm; Sustainability Performance: See ProductInformation (Technical PDF); WarrantyDescription: Manufacturer warranty, applicable worldwide, with the pertinent national legislation prevailing in all cases and covering at least a 3-year period; all products must have been manufactured and fitted in accordance with the Fabricator's Manual, and have been used and cared for in accordance with the Guide to Use, Cleaning and Care available on the web page www.porcelanosa.com; WarrantyDurationLabor: n/a; WarrantyDurationParts: 3; WarrantyDurationUnit: year; WarrantyGuarantorLabor: n/a; WarrantyGuarantorParts: bim.gp@porcelanosagrupo.com
Type - Pset_CoveringCommon - IsExternal: yes; Reference: n/a; AcousticRating: n/a; Finish: Tone Variations, Matte, Rectified, Wood; FireRating: A1; FlammabilityRating: Class 0; FragilityRating: n/a; Material: Ceramic; SurfaceSpreadOfFlame: Class 0; ThermalTransmittance: 200 kg/K/s3; TotalThickness: 11.5 mm
Type - IFC - IfcExportType: FLOORING; IfcExportAS: IfcCovering
Type - NBS_Data - HasSurfaceRoughness: no; AbrasionResistance: 4: Light-External Access; BreakingStrength: Average Value: 3310 N (Min. 1300 N); ChemicalResistance: Class 'A' for swimming pools and cleaning products (resists attack); minimum Class 'B' for acids and bases; Collection: PAR-KER; CreationDate: 2018/07; Dcof: >0.42; FlexuralStrength: >40 N/mm²; FrostResistance: Conforms to ISO 10545-9; Group: BIa; MoistureExpansion: <0.1 mm/m; RampTest: R-10; RecycledContent: >6.5%; Series: Ascot; SlipResistanceValuePendulumTestValue: CL1; StainResistance: Class 5: Easy cleaning with water; SurfaceQuality: Without surface defects; ThermalShockResistance: Conforms to ISO 10545–12; UpecC: n/a; UpecE: n/a; UpecP: n/a; UpecU: n/a; WaterAbsorption: E<=0.5%
COBie - AssetIdentifier: n/a; BarCode: n/a; InstallationDate: 1900-12-31T23:59:59; TagNumber: n/a; WarrantyStartDate: 1900-12-31T23:59:59

# IfcWallStandardCase: Basic Wall:PGR_Porcelanosa_CeramicTiles_Ascot_Roble-294x1200mm-100161122, Basic Wall:PGR_Porcelanosa_CeramicTiles_Ascot_Roble-294x1200mm-100161122:215114
In: Level 1
Type - PredefinedType: STANDARD; Material: PGR_Porcelanosa_CeramicTiles_Ascot_Roble-294x1200mm-100161122 11 mm
Type - NBS_General - Author: Porcelanosa Group; BIMObjectName: PGR_Porcelanosa_CeramicTiles_Ascot_Roble-294x1200mm-100161122; ManufacturerURL: www.porcelanosa.com; NBSDescription: Ceramic Tiles; NBSReference: 45-80-95/310; ProductInformation: http://calidad.info-grupo.com:8081/GeneraFicha3/PDF?articulo=100161122&lang=EN&un=0; Revision: n/a; Uniclass2015Code: Pr_35_93_96_19; Uniclass2015Title: Ceramic Tiles; Uniclass2015Version: Products v1.5; Version: 1
Type - COBie - AccessibilityPerformance: See ProductInformation (Technical PDF); AssetType: Fixed; Category: Walls; CodePerformance: ISO-13006:2012; UNE-EN 14411:2012; Color: Marron; Constituents: Clays, feldespat and glaze; Description: Rectified Porcelain tiles, ASCOT series from PORCELANOSA, MARRON color and MATTE finish, 29.4x120 cm (11.5 mm thickness), group BIa, according to UNE-EN 14411, water absortion capacity E<=0.5%, flexural strength >40 N/mm², breaking strength with an average value of 3310 N (Min. 1300 N) and slip resistance R-10; DurationUnit: year; ExpectedLife: 50; Features: See ProductInformation (Technical PDF); Grade: First quality; Manufacturer: bim.gp@porcelanosagrupo.com; ModelNumber: 100161122; ModelReference: Ascot Roble 29.4x120 cm; Name: CeramicTiles_Ascot_Roble-294x1200mm-100161122; NominalHeight: 11.5 mm; NominalLength: 1200 mm; NominalWidth: 294 mm; ReplacementCost: n/a; Shape: Rectangular; Size: 294x1200x11.5 mm; Sustainability Performance: See ProductInformation (Technical PDF); WarrantyDescription: Manufacturer warranty, applicable worldwide, with the pertinent national legislation prevailing in all cases and covering at least a 3-year period; all products must have been manufactured and fitted in accordance with the Fabricator's Manual, and have been used and cared for in accordance with the Guide to Use, Cleaning and Care available on the web page www.porcelanosa.com; WarrantyDurationLabor: n/a; WarrantyDurationParts: 3; WarrantyDurationUnit: year; WarrantyGuarantorLabor: n/a; WarrantyGuarantorParts: bim.gp@porcelanosagrupo.com
Type - Pset_CoveringCommon - IsExternal: yes; Reference: n/a; AcousticRating: n/a; Finish: Tone Variations, Matte, Rectified, Wood; FireRating: A1; FlammabilityRating: Class 0; FragilityRating: n/a; Material: Ceramic; SurfaceSpreadOfFlame: Class 0; ThermalTransmittance: 200 kg/K/s3; TotalThickness: 11.5 mm
Type - IFC - IfcExportType: FLOORING; IfcExportAS: IfcCovering
Type - NBS_Data - HasSurfaceRoughness: no; AbrasionResistance: 4: Light-External Access; BreakingStrength: Average Value: 3310 N (Min. 1300 N); ChemicalResistance: Class 'A' for swimming pools and cleaning products (resists attack); minimum Class 'B' for acids and bases; Collection: PAR-KER; CreationDate: 2018/07; Dcof: >0.42; FlexuralStrength: >40 N/mm²; FrostResistance: Conforms to ISO 10545-9; Group: BIa; MoistureExpansion: <0.1 mm/m; RampTest: R-10; RecycledContent: >6.5%; Series: Ascot; SlipResistanceValuePendulumTestValue: CL1; StainResistance: Class 5: Easy cleaning with water; SurfaceQuality: Without surface defects; ThermalShockResistance: Conforms to ISO 10545–12; UpecC: 2; UpecE: 3; UpecP: 3; UpecU: 2S; WaterAbsorption: E<=0.5%
COBie - AssetIdentifier: n/a; BarCode: n/a; InstallationDate: 1900-12-31T23:59:59; TagNumber: n/a; WarrantyStartDate: 1900-12-31T23:59:59

# IfcWallStandardCase: Basic Wall:PGR_Porcelanosa_CeramicTiles_Ascot_Roble_Ant.-193x1200mm-100161037, Basic Wall:PGR_Porcelanosa_CeramicTiles_Ascot_Roble_Ant.-193x1200mm-100161037:215115
In: Level 1
Type - PredefinedType: STANDARD; Material: PGR_Porcelanosa_CeramicTiles_Ascot_Roble_Ant.-193x1200mm-100161037 11 mm
Type - NBS_General - Author: Porcelanosa Group; BIMObjectName: PGR_Porcelanosa_CeramicTiles_Ascot_Roble_Ant.-193x1200mm-100161037; ManufacturerURL: www.porcelanosa.com; NBSDescription: Ceramic Tiles; NBSReference: 45-80-95/310; ProductInformation: http://calidad.info-grupo.com:8081/GeneraFicha3/PDF?articulo=100161037&lang=EN&un=0; Revision: n/a; Uniclass2015Code: Pr_35_93_96_19; Uniclass2015Title: Ceramic Tiles; Uniclass2015Version: Products v1.5; Version: 1
Type - COBie - AccessibilityPerformance: See ProductInformation (Technical PDF); AssetType: Fixed; Category: Walls; CodePerformance: ISO-13006:2012; UNE-EN 14411:2012; Color: Marron; Constituents: Clays, feldespat and glaze; Description: Rectified Porcelain tiles, ASCOT series from PORCELANOSA, MARRON color and MATTE finish, 19.3x120 cm (11.5 mm thickness), group BIa, according to UNE-EN 14411, water absortion capacity E<=0.5%, flexural strength >40 N/mm², breaking strength with an average value of 3310 N (Min. 1300 N) and slip resistance R-12; DurationUnit: year; ExpectedLife: 50; Features: See ProductInformation (Technical PDF); Grade: First quality; Manufacturer: bim.gp@porcelanosagrupo.com; ModelNumber: 100161037; ModelReference: Ascot Roble Ant. 19.3x120 cm; Name: CeramicTiles_Ascot_Roble_Ant.-193x1200mm-100161037; NominalHeight: 11.5 mm; NominalLength: 1200 mm; NominalWidth: 193 mm; ReplacementCost: n/a; Shape: Rectangular; Size: 193x1200x11.5 mm; Sustainability Performance: See ProductInformation (Technical PDF); WarrantyDescription: Manufacturer warranty, applicable worldwide, with the pertinent national legislation prevailing in all cases and covering at least a 3-year period; all products must have been manufactured and fitted in accordance with the Fabricator's Manual, and have been used and cared for in accordance with the Guide to Use, Cleaning and Care available on the web page www.porcelanosa.com; WarrantyDurationLabor: n/a; WarrantyDurationParts: 3; WarrantyDurationUnit: year; WarrantyGuarantorLabor: n/a; WarrantyGuarantorParts: bim.gp@porcelanosagrupo.com
Type - Pset_CoveringCommon - IsExternal: yes; Reference: n/a; AcousticRating: n/a; Finish: Tone Variations, Matte, Non-Slip, Rectified, Wood; FireRating: A1; FlammabilityRating: Class 0; FragilityRating: n/a; Material: Ceramic; SurfaceSpreadOfFlame: Class 0; ThermalTransmittance: 200 kg/K/s3; TotalThickness: 11.5 mm
Type - IFC - IfcExportType: FLOORING; IfcExportAS: IfcCovering
Type - NBS_Data - HasSurfaceRoughness: no; AbrasionResistance: 4: Light-External Access; BreakingStrength: Average Value: 3310 N (Min. 1300 N); ChemicalResistance: Class 'A' for swimming pools and cleaning products (resists attack); minimum Class 'B' for acids and bases; Collection: PAR-KER; CreationDate: 2018/07; Dcof: >0.42; FlexuralStrength: >40 N/mm²; FrostResistance: Conforms to ISO 10545-9; Group: BIa; MoistureExpansion: <0.1 mm/m; RampTest: R-12; RecycledContent: >6.5%; Series: Ascot; SlipResistanceValuePendulumTestValue: CL3; StainResistance: Class 5: Easy cleaning with water; SurfaceQuality: Without surface defects; ThermalShockResistance: Conforms to ISO 10545–12; UpecC: n/a; UpecE: n/a; UpecP: n/a; UpecU: n/a; WaterAbsorption: E<=0.5%
COBie - AssetIdentifier: n/a; BarCode: n/a; InstallationDate: 1900-12-31T23:59:59; TagNumber: n/a; WarrantyStartDate: 1900-12-31T23:59:59

# IfcWallStandardCase: Basic Wall:PGR_Porcelanosa_CeramicTiles_Ascot_Teca-193x1200mm-100161038, Basic Wall:PGR_Porcelanosa_CeramicTiles_Ascot_Teca-193x1200mm-100161038:209151
In: Level 1
Type - PredefinedType: STANDARD; Material: PGR_Porcelanosa_CeramicTiles_Ascot_Teca-193x1200mm-100161038 12 mm
Type - NBS_General - Author: Porcelanosa Group; BIMObjectName: PGR_Porcelanosa_CeramicTiles_Ascot_Teca-193x1200mm-100161038; ManufacturerURL: www.porcelanosa.com; NBSDescription: Ceramic Tiles; NBSReference: 45-80-95/310; ProductInformation: http://calidad.info-grupo.com:8081/GeneraFicha3/PDF?articulo=100161038&lang=EN&un=0; Revision: n/a; Uniclass2015Code: Pr_35_93_96_19; Uniclass2015Title: Ceramic Tiles; Uniclass2015Version: Products v1.5; Version: 1
Type - COBie - AccessibilityPerformance: See ProductInformation (Technical PDF); AssetType: Fixed; Category: Pr_35_93_96_19:Ceramic Tiles; CodePerformance: ISO-13006:2012; UNE-EN 14411:2012; Color: Marron; Constituents: Clays, feldespat and glaze; Description: Rectified Porcelain tiles, ASCOT series from PORCELANOSA, MARRON color and MATTE finish, 19.3x120 cm (11.5 mm thickness), group BIa, according to UNE-EN 14411, water absortion capacity E<=0.5%, flexural strength >40 N/mm², breaking strength with an average value of 3310 N (Min. 1300 N) and slip resistance R-10; DurationUnit: year; ExpectedLife: 50; Features: See ProductInformation (Technical PDF); Grade: First quality; Manufacturer: bim.gp@porcelanosagrupo.com; ModelNumber: 100161038; ModelReference: Ascot Teca 19.3x120 cm; Name: CeramicTiles_Ascot_Teca-193x1200mm-100161038; NominalHeight: 11.5 mm; NominalLength: 1200 mm; NominalWidth: 193 mm; ReplacementCost: n/a; Shape: Rectangular; Size: 193x1200x11.5 mm; Sustainability Performance: See ProductInformation (Technical PDF); WarrantyDescription: Manufacturer warranty, applicable worldwide, with the pertinent national legislation prevailing in all cases and covering at least a 3-year period; all products must have been manufactured and fitted in accordance with the Fabricator's Manual, and have been used and cared for in accordance with the Guide to Use, Cleaning and Care available on the web page www.porcelanosa.com; WarrantyDurationLabor: n/a; WarrantyDurationParts: 3; WarrantyDurationUnit: year; WarrantyGuarantorLabor: n/a; WarrantyGuarantorParts: bim.gp@porcelanosagrupo.com
Type - Pset_CoveringCommon - IsExternal: yes; Reference: n/a; AcousticRating: n/a; Finish: Tone Variations, Matte, Rectified, Wood; FireRating: A1; FlammabilityRating: Class 0; FragilityRating: n/a; Material: Ceramic; SurfaceSpreadOfFlame: Class 0; ThermalTransmittance: 200 kg/K/s3; TotalThickness: 11.5 mm
Type - IFC - IfcExportType: FLOORING; IfcExportAS: IfcCovering
Type - NBS_Data - HasSurfaceRoughness: no; AbrasionResistance: 4: Light-External Access; BreakingStrength: Average Value: 3310 N (Min. 1300 N); ChemicalResistance: Class 'A' for swimming pools and cleaning products (resists attack); minimum Class 'B' for acids and bases; Collection: PAR-KER; CreationDate: 2018/07; Dcof: >0.42; FlexuralStrength: >40 N/mm²; FrostResistance: Conforms to ISO 10545-9; Group: BIa; MoistureExpansion: <0.1 mm/m; RampTest: R-10; RecycledContent: >6.5%; Series: Ascot; SlipResistanceValuePendulumTestValue: CL1; StainResistance: Class 5: Easy cleaning with water; SurfaceQuality: Without surface defects; ThermalShockResistance: Conforms to ISO 10545–12; UpecC: n/a; UpecE: n/a; UpecP: n/a; UpecU: n/a; WaterAbsorption: E<=0.5%
COBie - AssetIdentifier: n/a; BarCode: n/a; InstallationDate: 1900-12-31T23:59:59; TagNumber: n/a; WarrantyStartDate: 1900-12-31T23:59:59

# IfcWallStandardCase: Basic Wall:PGR_Porcelanosa_CeramicTiles_Ascot_Teca-294x1200mm-100161123, Basic Wall:PGR_Porcelanosa_CeramicTiles_Ascot_Teca-294x1200mm-100161123:202329
In: Level 1
Type - PredefinedType: STANDARD; Material: PGR_Porcelanosa_CeramicTiles_Ascot_Teca-294x1200mm-100161123 12 mm
Type - NBS_General - Author: Porcelanosa Group; BIMObjectName: PGR_Porcelanosa_CeramicTiles_Ascot_Teca-294x1200mm-100161123; ManufacturerURL: www.porcelanosa.com; NBSDescription: Ceramic Tiles; NBSReference: 45-80-95/310; ProductInformation: http://calidad.info-grupo.com:8081/GeneraFicha3/PDF?articulo=100161123&lang=EN&un=0; Revision: n/a; Uniclass2015Code: Pr_35_93_96_19; Uniclass2015Title: Ceramic Tiles; Uniclass2015Version: Products v1.5; Version: 1
Type - COBie - AccessibilityPerformance: See ProductInformation (Technical PDF); AssetType: Fixed; Category: Walls; CodePerformance: ISO-13006:2012; UNE-EN 14411:2012; Color: Marron; Constituents: Clays, feldespat and glaze; Description: Rectified Porcelain tiles, ASCOT series from PORCELANOSA, MARRON color and MATTE finish, 29.4x120 cm (11.5 mm thickness), group BIa, according to UNE-EN 14411, water absortion capacity E<=0.5%, flexural strength >40 N/mm², breaking strength with an average value of 3310 N (Min. 1300 N) and slip resistance R-10; DurationUnit: year; ExpectedLife: 50; Features: See ProductInformation (Technical PDF); Grade: First quality; Manufacturer: bim.gp@porcelanosagrupo.com; ModelNumber: 100161123; ModelReference: Ascot Teca 29.4x120 cm; Name: CeramicTiles_Ascot_Teca-294x1200mm-100161123; NominalHeight: 11.5 mm; NominalLength: 1200 mm; NominalWidth: 294 mm; ReplacementCost: n/a; Shape: Rectangular; Size: 294x1200x11.5 mm; Sustainability Performance: See ProductInformation (Technical PDF); WarrantyDescription: Manufacturer warranty, applicable worldwide, with the pertinent national legislation prevailing in all cases and covering at least a 3-year period; all products must have been manufactured and fitted in accordance with the Fabricator's Manual, and have been used and cared for in accordance with the Guide to Use, Cleaning and Care available on the web page www.porcelanosa.com; WarrantyDurationLabor: n/a; WarrantyDurationParts: 3; WarrantyDurationUnit: year; WarrantyGuarantorLabor: n/a; WarrantyGuarantorParts: bim.gp@porcelanosagrupo.com
Type - Pset_CoveringCommon - IsExternal: yes; Reference: n/a; AcousticRating: n/a; Finish: Tone Variations, Matte, Rectified, Wood; FireRating: A1; FlammabilityRating: Class 0; FragilityRating: n/a; Material: Ceramic; SurfaceSpreadOfFlame: Class 0; ThermalTransmittance: 200 kg/K/s3; TotalThickness: 11.5 mm
Type - IFC - IfcExportType: FLOORING; IfcExportAS: IfcCovering
Type - NBS_Data - HasSurfaceRoughness: no; AbrasionResistance: 4: Light-External Access; BreakingStrength: Average Value: 3310 N (Min. 1300 N); ChemicalResistance: Class 'A' for swimming pools and cleaning products (resists attack); minimum Class 'B' for acids and bases; Collection: PAR-KER; CreationDate: 2018/07; Dcof: >0.42; FlexuralStrength: >40 N/mm²; FrostResistance: Conforms to ISO 10545-9; Group: BIa; MoistureExpansion: <0.1 mm/m; RampTest: R-10; RecycledContent: >6.5%; Series: Ascot; SlipResistanceValuePendulumTestValue: CL1; StainResistance: Class 5: Easy cleaning with water; SurfaceQuality: Without surface defects; ThermalShockResistance: Conforms to ISO 10545–12; UpecC: 2; UpecE: 3; UpecP: 3; UpecU: 2S; WaterAbsorption: E<=0.5%
COBie - AssetIdentifier: n/a; BarCode: n/a; InstallationDate: 1900-12-31T23:59:59; TagNumber: n/a; WarrantyStartDate: 1900-12-31T23:59:59

# IfcWallStandardCase: Basic Wall:PGR_Porcelanosa_CeramicTiles_Ascot_Teca_Ant.-193x1200mm-100161039, Basic Wall:PGR_Porcelanosa_CeramicTiles_Ascot_Teca_Ant.-193x1200mm-100161039:213204
In: Level 1
Type - PredefinedType: STANDARD; Material: PGR_Porcelanosa_CeramicTiles_Ascot_Teca_Ant.-193x1200mm-100161039 12 mm
Type - NBS_General - Author: Porcelanosa Group; BIMObjectName: PGR_Porcelanosa_CeramicTiles_Ascot_Teca_Ant.-193x1200mm-100161039; ManufacturerURL: www.porcelanosa.com; NBSDescription: Ceramic Tiles; NBSReference: 45-80-95/310; ProductInformation: http://calidad.info-grupo.com:8081/GeneraFicha3/PDF?articulo=100161039&lang=EN&un=0; Revision: n/a; Uniclass2015Code: Pr_35_93_96_19; Uniclass2015Title: Ceramic Tiles; Uniclass2015Version: Products v1.5; Version: 1
Type - COBie - AccessibilityPerformance: See ProductInformation (Technical PDF); AssetType: Fixed; Category: Pr_35_93_96_19:Ceramic Tiles; CodePerformance: ISO-13006:2012; UNE-EN 14411:2012; Color: Marron; Constituents: Clays, feldespat and glaze; Description: Rectified Porcelain tiles, ASCOT series from PORCELANOSA, MARRON color and MATTE finish, 19.3x120 cm (11.5 mm thickness), group BIa, according to UNE-EN 14411, water absortion capacity E<=0.5%, flexural strength >40 N/mm², breaking strength with an average value of 3310 N (Min. 1300 N) and slip resistance R-12; DurationUnit: year; ExpectedLife: 50; Features: See ProductInformation (Technical PDF); Grade: First quality; Manufacturer: bim.gp@porcelanosagrupo.com; ModelNumber: 100161039; ModelReference: Ascot Teca Ant. 19.3x120 cm; Name: CeramicTiles_Ascot_Teca_Ant.-193x1200mm-100161039; NominalHeight: 11.5 mm; NominalLength: 1200 mm; NominalWidth: 193 mm; ReplacementCost: n/a; Shape: Rectangular; Size: 193x1200x11.5 mm; Sustainability Performance: See ProductInformation (Technical PDF); WarrantyDescription: Manufacturer warranty, applicable worldwide, with the pertinent national legislation prevailing in all cases and covering at least a 3-year period; all products must have been manufactured and fitted in accordance with the Fabricator's Manual, and have been used and cared for in accordance with the Guide to Use, Cleaning and Care available on the web page www.porcelanosa.com; WarrantyDurationLabor: n/a; WarrantyDurationParts: 3; WarrantyDurationUnit: year; WarrantyGuarantorLabor: n/a; WarrantyGuarantorParts: bim.gp@porcelanosagrupo.com
Type - Pset_CoveringCommon - IsExternal: yes; Reference: n/a; AcousticRating: n/a; Finish: Tone Variations, Matte, Non-Slip, Rectified, Wood; FireRating: A1; FlammabilityRating: Class 0; FragilityRating: n/a; Material: Ceramic; SurfaceSpreadOfFlame: Class 0; ThermalTransmittance: 200 kg/K/s3; TotalThickness: 11.5 mm
Type - IFC - IfcExportType: FLOORING; IfcExportAS: IfcCovering
Type - NBS_Data - HasSurfaceRoughness: no; AbrasionResistance: 4: Light-External Access; BreakingStrength: Average Value: 3310 N (Min. 1300 N); ChemicalResistance: Class 'A' for swimming pools and cleaning products (resists attack); minimum Class 'B' for acids and bases; Collection: PAR-KER; CreationDate: 2018/07; Dcof: >0.42; FlexuralStrength: >40 N/mm²; FrostResistance: Conforms to ISO 10545-9; Group: BIa; MoistureExpansion: <0.1 mm/m; RampTest: R-12; RecycledContent: >6.5%; Series: Ascot; SlipResistanceValuePendulumTestValue: CL3; StainResistance: Class 5: Easy cleaning with water; SurfaceQuality: Without surface defects; ThermalShockResistance: Conforms to ISO 10545–12; UpecC: n/a; UpecE: n/a; UpecP: n/a; UpecU: n/a; WaterAbsorption: E<=0.5%
COBie - AssetIdentifier: n/a; BarCode: n/a; InstallationDate: 1900-12-31T23:59:59; TagNumber: n/a; WarrantyStartDate: 1900-12-31T23:59:59
